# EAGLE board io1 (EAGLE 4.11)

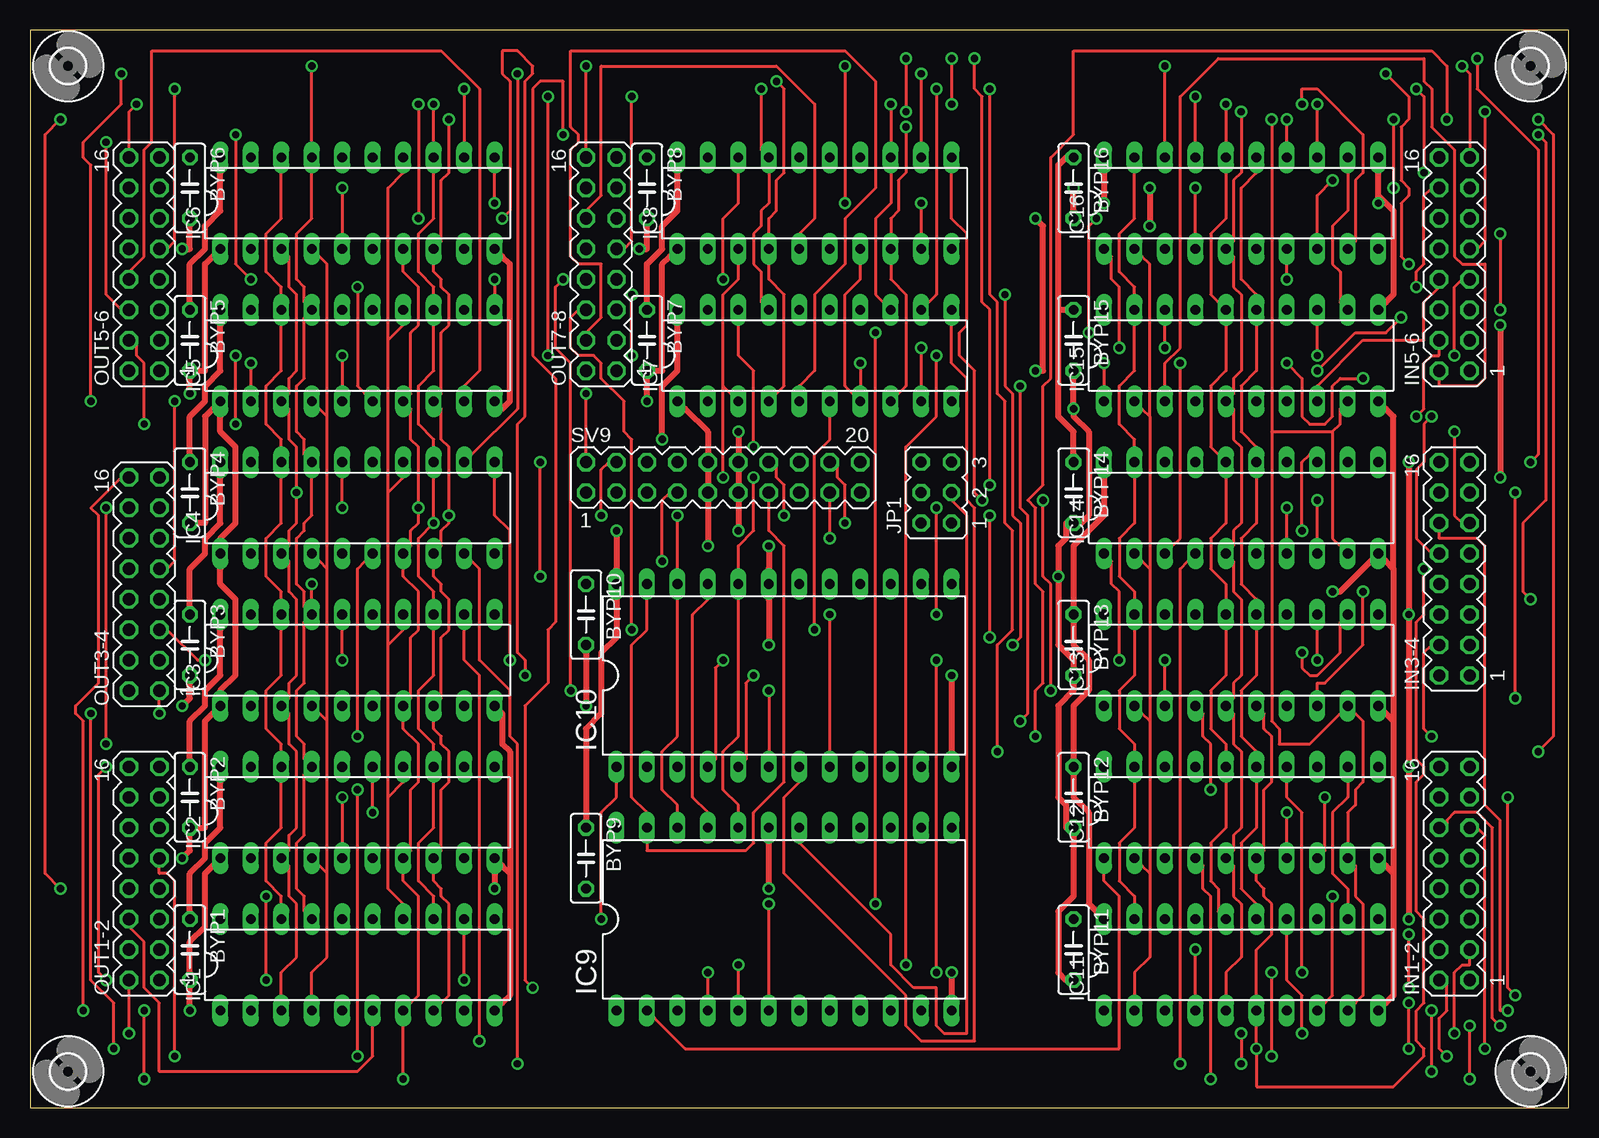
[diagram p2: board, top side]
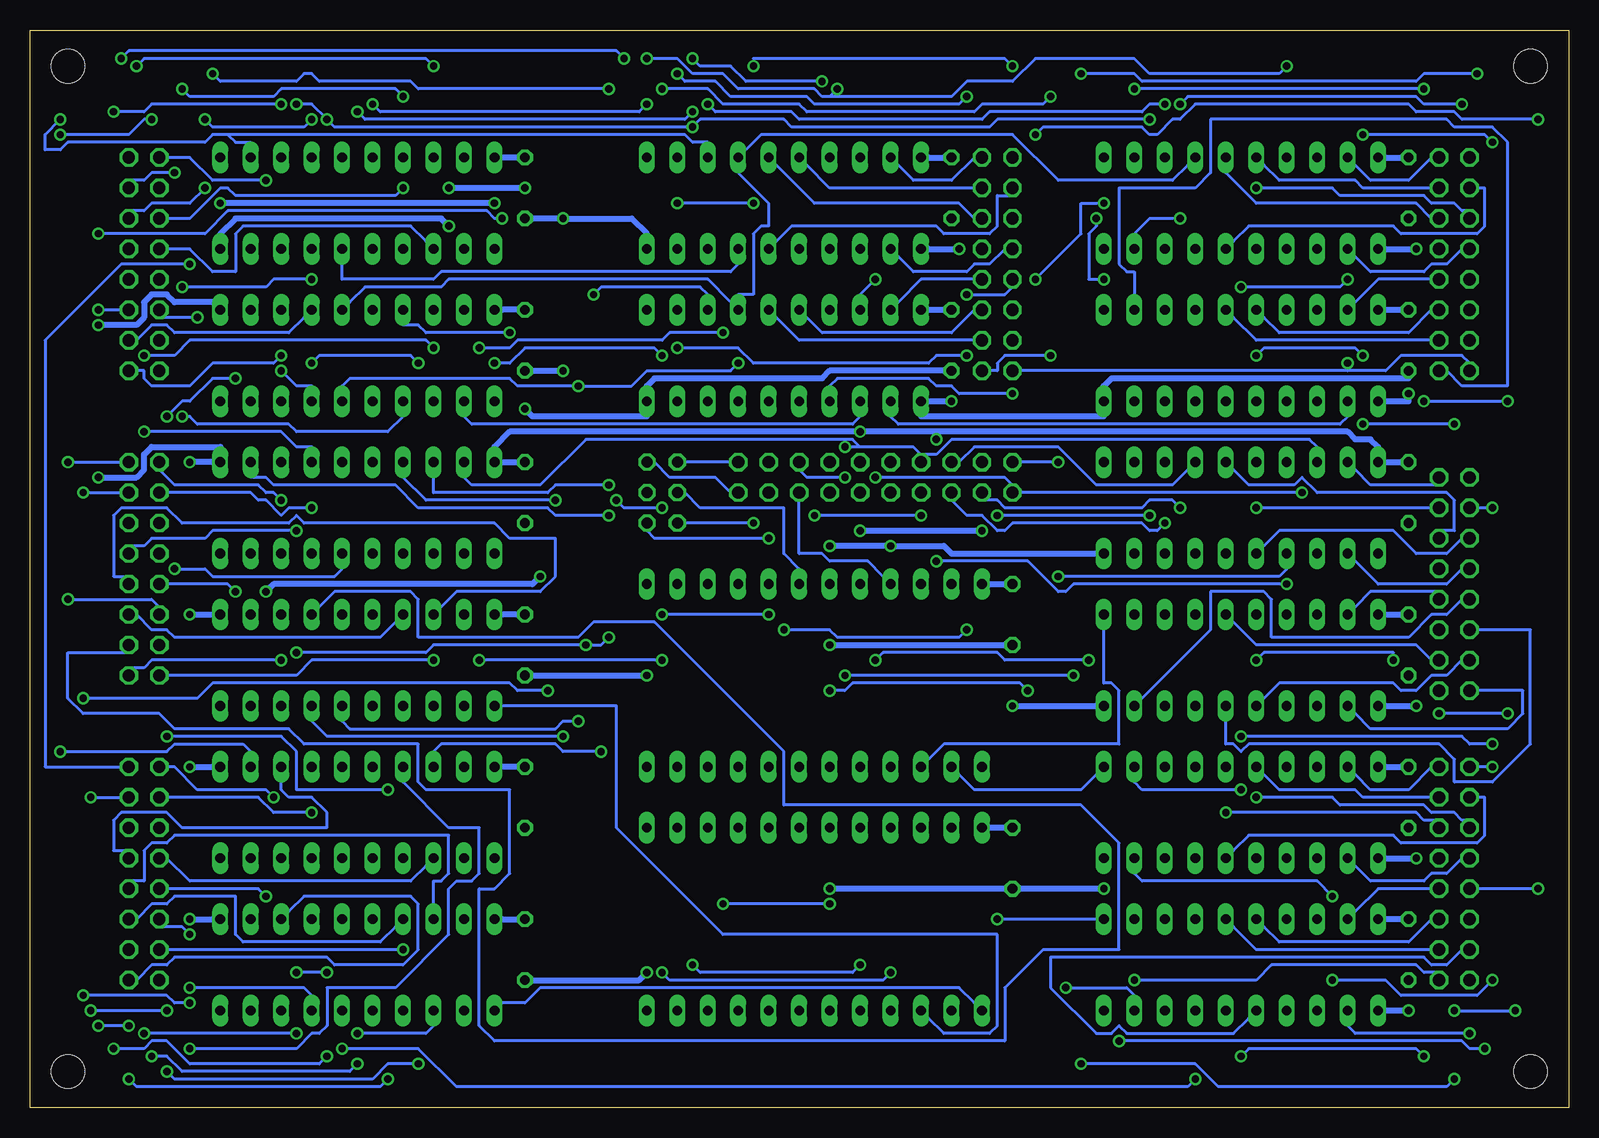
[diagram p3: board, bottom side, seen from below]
Size 128.25 x 89.84 mm. Coordinates in mm from the lower left corner, seen from the top.
Outline: 0,0 128.25,0 128.25,89.84 0,89.84 0,0
Copper layers (1*16): Top 0.035mm / dielectric 1.5mm / Bottom 0.035mm
Design rules "default": minimum track width 10mil, minimum drill 24mil, track to track 8mil, track to pad 8mil, pad to pad 8mil, via to via 8mil, smd to smd 8mil, copper to edge 40mil, drill to drill 8mil, minimum pad ring 10mil, minimum via ring 8mil, stop-mask expansion 4mil, vias tented up to drill 0mil, thermal gap 10mil
Net classes: 1 Power: width 0.508 mm, drill 0.254 mm, clearance 0.254 mm

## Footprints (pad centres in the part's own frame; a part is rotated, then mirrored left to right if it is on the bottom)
C050-025X075 = drill 0.813 octagon: 1 -2.54,0; 2 2.54,0
DIL20 = drill 0.813 long: 1 -11.43,-3.81; 2 -8.89,-3.81; 3 -6.35,-3.81; 4 -3.81,-3.81; 5 -1.27,-3.81; 6 1.27,-3.81; 7 3.81,-3.81; 8 6.35,-3.81; 9 8.89,-3.81; 10 11.43,-3.81; 11 11.43,3.81; 12 8.89,3.81; 13 6.35,3.81; 14 3.81,3.81; 15 1.27,3.81; 16 -1.27,3.81; 17 -3.81,3.81; 18 -6.35,3.81; 19 -8.89,3.81; 20 -11.43,3.81
DIL24-6 = drill 0.813 long: 1 -13.97,-7.62; 2 -11.43,-7.62; 3 -8.89,-7.62; 4 -6.35,-7.62; 5 -3.81,-7.62; 6 -1.27,-7.62; 7 1.27,-7.62; 8 3.81,-7.62; 9 6.35,-7.62; 10 8.89,-7.62; 11 11.43,-7.62; 12 13.97,-7.62; 13 13.97,7.62; 14 11.43,7.62; 15 8.89,7.62; 16 6.35,7.62; 17 3.81,7.62; 18 1.27,7.62; 19 -1.27,7.62; 20 -3.81,7.62; 21 -6.35,7.62; 22 -8.89,7.62; 23 -11.43,7.62; 24 -13.97,7.62
MA08-2 = drill 1.016 octagon: 1 -8.89,-1.27; 2 -8.89,1.27; 3 -6.35,-1.27; 4 -6.35,1.27; 5 -3.81,-1.27; 6 -3.81,1.27; 7 -1.27,-1.27; 8 -1.27,1.27; 9 1.27,-1.27; 10 1.27,1.27; 11 3.81,-1.27; 12 3.81,1.27; 13 6.35,-1.27; 14 6.35,1.27; 15 8.89,-1.27; 16 8.89,1.27
JP3Q = drill 0.914 octagon: 1 -2.54,-1.27; 2 -2.54,1.27; 3 0,-1.27; 4 0,1.27; 5 2.54,-1.27; 6 2.54,1.27
MA10-2 = drill 1.016 octagon: 1 -11.43,-1.27; 2 -11.43,1.27; 3 -8.89,-1.27; 4 -8.89,1.27; 5 -6.35,-1.27; 6 -6.35,1.27; 7 -3.81,-1.27; 8 -3.81,1.27; 9 -1.27,-1.27; 10 -1.27,1.27; 11 1.27,-1.27; 12 1.27,1.27; 13 3.81,-1.27; 14 3.81,1.27; 15 6.35,-1.27; 16 6.35,1.27; 17 8.89,-1.27; 18 8.89,1.27; 19 11.43,-1.27; 20 11.43,1.27
2,8 = hole 2.8: 0,0

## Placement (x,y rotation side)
BYP1  .01uf  [C050-025X075]  13.33,13.17 270 top
BYP2  .01uf  [C050-025X075]  13.33,25.87 270 top
BYP3  .01uf  [C050-025X075]  13.33,38.57 270 top
BYP4  .01uf  [C050-025X075]  13.33,51.27 270 top
BYP5  .01uf  [C050-025X075]  13.33,63.97 270 top
BYP6  .01uf  [C050-025X075]  13.33,76.67 270 top
BYP7  .01uf  [C050-025X075]  51.43,63.97 270 top
BYP8  .01uf  [C050-025X075]  51.43,76.67 270 top
BYP9  .01uf  [C050-025X075]  46.35,20.79 270 top
BYP10  .01uf  [C050-025X075]  46.35,41.11 270 top
BYP11  .01uf  [C050-025X075]  86.99,13.17 270 top
BYP12  .01uf  [C050-025X075]  86.99,25.87 270 top
BYP13  .01uf  [C050-025X075]  86.99,38.57 270 top
BYP14  .01uf  [C050-025X075]  86.99,51.27 270 top
BYP15  .01uf  [C050-025X075]  86.99,63.97 270 top
BYP16  .01uf  [C050-025X075]  86.99,76.67 270 top
IC1  74LS374N  [DIL20]  27.3,11.9 0 top
IC2  74LS374N  [DIL20]  27.3,24.6 0 top
IC3  74LS374N  [DIL20]  27.3,37.3 0 top
IC4  74LS374N  [DIL20]  27.3,50 0 top
IC5  74LS374N  [DIL20]  27.3,62.7 0 top
IC6  74LS374N  [DIL20]  27.3,75.4 0 top
IC7  74LS374N  [DIL20]  65.4,62.7 0 top
IC8  74LS374N  [DIL20]  65.4,75.4 0 top
IC9  74154N  [DIL24-6]  62.86,15.71 0 top
IC10  74154N  [DIL24-6]  62.86,36.03 0 top
IC11  74LS373N  [DIL20]  100.96,11.9 0 top
IC12  74LS373N  [DIL20]  100.96,24.6 0 top
IC13  74LS373N  [DIL20]  100.96,37.3 0 top
IC14  74LS373N  [DIL20]  100.96,50 0 top
IC15  74LS373N  [DIL20]  100.96,62.7 0 top
IC16  74LS373N  [DIL20]  100.96,75.4 0 top
IN1-2  [MA08-2]  118.74,19.52 90 top
IN3-4  [MA08-2]  118.74,44.92 90 top
IN5-6  [MA08-2]  118.74,70.32 90 top
JP1  [JP3Q]  75.56,51.27 90 top
OUT1-2  [MA08-2]  9.52,19.52 90 top
OUT3-4  [MA08-2]  9.52,43.65 90 top
OUT5-6  [MA08-2]  9.52,70.32 90 top
OUT7-8  [MA08-2]  47.62,70.32 90 top
SV9  [MA10-2]  57.78,52.54 0 top
U$1  [2,8]  125.09,3.01 0 top
U$2  [2,8]  125.09,86.83 0 top
U$3  [2,8]  3.17,86.83 0 top
U$4  [2,8]  3.17,3.01 0 top

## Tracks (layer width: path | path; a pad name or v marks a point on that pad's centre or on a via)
GND  (via drill 0.61)
  Top 0.508: 113.66,19.52 113.66,9.36 113.02,8.73 IC11.10 | 113.66,19.52 113.02,20.15 IC12.10 | 113.66,32.22 113.02,32.85 IC13.10 | 113.66,32.22 113.66,19.52 | 113.66,44.92 113.02,45.55 IC14.10 111.75,45.55 109.21,43.02 v108.58,43.02 | 113.66,44.92 113.66,32.22 | 113.66,44.92 113.66,57.62 113.02,58.25 IC15.10 | v76.83,11.27 76.83,9.36 IC9.12 | v76.83,36.03 76.83,29.68 IC10.12 | BYP11.2 86.35,10.63 85.72,11.27 85.72,16.34 86.99,17.61 86.99,22.7 BYP12.2 86.35,23.33 86.35,25.23 85.72,25.87 85.72,33.49 86.99,34.76 86.99,35.39 BYP13.2 86.99,36.66 86.99,37.3 85.72,38.57 v85.72,44.28 85.72,46.82 86.35,47.46 86.35,48.73 BYP14.2 87.62,48.73 88.26,49.37 88.26,56.35 86.99,57.62 v86.99,58.25 86.99,60.8 BYP15.2 | v93.34,76.67 v93.34,73.5 | v86.99,76.67 86.99,74.77 BYP16.2 | v83.81,61.43 84.45,61.43 84.45,73.5 v83.81,74.13 | v12.7,33.49 13.33,34.12 13.33,35.39 BYP3.2 | v13.33,8.09 13.33,10 BYP1.2 13.33,11.27 13.33,13.81 14.6,15.08 14.6,19.52 15.24,20.15 IC2.1 | v12.7,20.79 13.33,21.42 13.33,22.7 BYP2.2 13.97,23.33 14.6,23.33 14.6,32.22 15.24,32.85 IC3.1 15.87,34.76 17.14,36.03 17.14,42.38 15.87,43.65 15.87,44.92 IC4.1 15.87,47.46 17.14,48.73 17.14,55.08 15.87,56.35 15.87,57.62 IC5.1 15.24,58.25 14.6,57.62 14.6,48.73 13.97,48.73 BYP4.2 | v12.7,71.59 13.33,71.59 13.33,73.5 BYP6.2 | v13.33,59.52 13.33,60.8 BYP5.2 13.97,61.43 14.6,61.43 14.6,70.32 15.24,70.95 IC6.1 | 40,19.52 40,9.36 39.37,8.73 IC1.10 | 40,19.52 39.37,20.15 IC2.10 38.73,19.52 v38.73,18.25 | v61.59,18.25 61.59,22.06 IC9.19 | v50.8,71.59 51.43,71.59 51.43,73.5 BYP8.2 | IC6.10 39.37,70.95 40,70.32 40,58.89 39.37,58.25 IC5.10
  Top 0.508: v51.43,58.89 51.43,60.8 BYP7.2 52.07,61.43 52.7,61.43 52.7,70.32 53.34,70.95 IC8.1 | v46.35,33.49 46.35,37.94 BYP10.2 | v56.51,46.82 56.51,50.63 SV9.9 56.51,51.91 56.51,53.17 SV9.10 56.51,54.45 56.51,56.35 54.61,58.25 IC7.1 | v61.59,46.82 61.59,44.92 IC10.19 61.59,42.38 v61.59,38.57 | 40,19.52 40,29.68 39.37,30.31 39.37,32.85 IC3.10
  Bottom 0.508: v76.83,11.27 77.46,10.63 86.35,10.63 BYP11.2 | v76.83,36.03 86.35,36.03 BYP13.2 | v86.99,58.25 86.35,57.62 76.83,57.62 IC7.10 76.83,60.16 76.19,60.8 62.23,60.8 61.59,61.43 52.07,61.43 BYP7.2 | IC8.10 76.83,72.86 78.1,74.13 v83.81,74.13 86.35,74.13 BYP16.2 | v93.34,73.5 93.97,74.13 111.12,74.13 112.39,72.86 IC16.10 | v86.99,76.67 v93.34,76.67 | v83.81,61.43 86.35,61.43 BYP15.2 | v108.58,43.02 107.94,43.65 86.35,43.65 v85.72,44.28 | v12.7,33.49 15.24,33.49 IC3.1 | v13.33,8.09 15.24,8.09 IC1.1 | v12.7,20.79 15.24,20.79 IC2.1 | v12.7,71.59 15.24,71.59 IC6.1 | v13.33,59.52 13.33,58.89 15.24,58.89 IC5.1 | v38.73,18.25 45.72,18.25 BYP9.2 46.98,18.25 v61.59,18.25 | v50.8,71.59 53.34,71.59 IC8.1 | v51.43,58.89 53.34,58.89 IC7.1 53.97,57.62 38.73,57.62 IC5.10 38.73,60.16 38.1,60.8 13.33,60.8 BYP5.2 | v46.35,33.49 39.37,33.49 IC3.10 | IC4.10 39.37,46.19 51.43,46.19 52.07,46.82 v56.51,46.82 v61.59,46.82 | v61.59,38.57 46.98,38.57 BYP10.2
IN00
  Bottom 0.254: IC9.1 49.53,8.73 50.8,10 85.72,10 86.99,8.73 88.89,8.73 IC11.1
IN01
  Top 0.254: IC9.2 52.07,7.46 54.61,4.92 90.8,4.92 90.8,17.61 89.53,18.88 89.53,19.52 IC12.1
IN02
  Bottom 0.254: IC9.3 53.34,7.46 52.07,6.18 48.26,6.18 47.62,6.82 47.62,14.44 70.48,14.44 79.37,23.33 79.37,33.49 88.89,33.49 IC13.1
IN03  (via drill 0.61)
  Top 0.254: v56.51,11.27 56.51,9.36 IC9.4 | v75.56,11.27 v75.56,37.3 | v90.8,37.3 90.8,43.02 90.16,43.65 90.16,45.55 IC14.1
  Bottom 0.254: v56.51,11.27 57.15,10.63 74.92,10.63 v75.56,11.27 | v75.56,37.3 v90.8,37.3
IN04  (via drill 0.61)
  Top 0.254: v59.05,11.9 59.05,9.36 IC9.5 | v73.02,11.9 73.02,55.08 75.56,57.62 v75.56,62.7 | v89.53,62.06 89.53,60.16 IC15.1
  Bottom 0.254: v59.05,11.9 59.69,11.27 72.38,11.27 v73.02,11.9 | v75.56,62.7 76.19,63.34 86.99,63.34 88.26,62.06 v89.53,62.06
IN05  (via drill 0.61)
  Top 0.254: v61.59,16.98 61.59,9.36 IC9.6 | v70.48,16.98 v70.48,64.61 | v90.8,63.34 90.8,68.41 90.16,69.05 90.16,70.95 IC16.1
  Bottom 0.254: v61.59,16.98 v70.48,16.98 | v70.48,64.61 74.92,64.61 75.56,63.97 87.62,63.97 88.26,63.34 v90.8,63.34
ISEL
  Top 0.254: IC9.18 64.13,22.06 71.75,14.44 71.75,11.9 73.66,10 75.56,10 75.56,6.82 76.19,6.18 78.1,6.18 78.1,49.37 76.83,50.63 JP1.3
N$1
  Bottom 0.254: IC12.3 95.24,20.15 96.52,18.88 114.93,18.88 116.83,20.79 IN1-2.10
N$2  (via drill 0.61)
  Top 0.254: v98.42,2.38 98.42,17.61 97.78,18.25 97.78,20.15 IC12.4 | v120.01,2.38 v120.01,6.82 | v122.55,6.82 121.91,7.46 121.91,23.33 120.64,24.6 118.74,24.6 118.1,23.96 118.1,23.33 IN1-2.12
  Bottom 0.254: v98.42,2.38 99.05,1.74 119.38,1.74 v120.01,2.38 | v120.01,6.82 v122.55,6.82
N$7  (via drill 0.61)
  Top 0.254: v104.77,24.6 104.77,22.06 IC12.7
  Bottom 0.254: v104.77,24.6 107.94,24.6 109.21,25.87 116.83,25.87 IN1-2.14
N$8  (via drill 0.61)
  Top 0.254: v107.94,25.87 107.94,21.42 IC12.8
  Bottom 0.254: v107.94,25.87 108.58,26.5 114.3,26.5 116.2,28.41 116.83,28.41 IN1-2.16
N$9  (via drill 0.61)
  Top 0.254: v108.58,17.61 108.58,9.36 107.94,8.73 IC11.8
  Bottom 0.254: v108.58,17.61 109.21,18.25 116.83,18.25 IN1-2.8
N$10  (via drill 0.61)
  Top 0.254: v114.93,10 v114.93,14.44
  Bottom 0.254: v114.93,14.44 115.56,15.08 117.47,15.08 IN1-2.6 | v114.93,10 105.41,10 104.77,9.36 IC11.7
N$11  (via drill 0.61)
  Top 0.254: v97.15,13.17 97.15,9.36 IC11.4
  Bottom 0.254: v97.15,13.17 116.83,13.17 IN1-2.4
N$12  (via drill 0.61)
  Top 0.254: v100.96,6.18 v100.96,3.64 | v118.1,4.28 117.47,4.92 117.47,7.46 118.1,8.09 118.1,10.63 IN1-2.2
  Bottom 0.254: v100.96,6.18 95.24,6.18 94.61,6.82 IC11.3 | v100.96,3.64 101.59,3.01 115.56,3.01 116.83,4.28 v118.1,4.28
N$13
  Bottom 0.254: IC11.13 106.67,16.34 105.41,17.61 96.52,17.61 95.88,16.98 95.88,13.17 97.15,11.9 102.86,11.9 103.5,12.54 116.2,12.54 116.83,11.9 118.1,11.9 119.38,10.63 IN1-2.1
N$14  (via drill 0.61)
  Top 0.254: v106.04,6.18 106.04,9.36 104.77,10.63 104.77,14.44 IC11.14 | v118.74,6.18 118.74,11.27 119.38,11.9 120.01,11.9 120.01,12.54 IN1-2.3
  Bottom 0.254: v106.04,6.18 v118.74,6.18
N$15
  Bottom 0.254: IC11.17 97.78,15.08 99.05,13.81 110.48,13.81 111.12,14.44 111.12,17.61 116.2,17.61 116.83,16.98 118.1,16.98 119.38,15.71 IN1-2.5
N$16
  Bottom 0.254: IC11.18 94.61,16.98 94.61,18.88 93.97,18.88 93.34,19.52 93.34,22.7 116.2,22.7 116.83,22.06 118.1,22.06 118.74,21.42 118.74,18.88 120.01,18.88 IN1-2.7
N$17
  Bottom 0.254: IC12.13 107.31,27.14 107.31,26.5 106.67,25.87 104.77,25.87 103.5,24.6 103.5,23.33 115.56,23.33 116.83,24.6 120.64,24.6 121.28,23.96 121.28,21.42 120.01,21.42 IN1-2.9
N$18  (via drill 0.61)
  Top 0.254: v121.28,4.92 121.28,22.7 120.64,23.33 IN1-2.11 | v103.5,4.28 v103.5,11.27 | v106.04,11.27 106.04,24.6 104.77,25.87 104.77,27.14 IC12.14
  Bottom 0.254: v121.28,4.92 118.74,4.92 118.1,5.55 116.83,5.55 114.93,3.64 104.13,3.64 v103.5,4.28 | v103.5,11.27 v106.04,11.27
N$19  (via drill 0.61)
  Top 0.254: v123.19,25.87 123.19,10 v123.82,9.36 | v114.93,4.92 v114.93,8.73
  Bottom 0.254: v123.19,25.87 120.64,25.87 IN1-2.13 | v123.82,9.36 116.83,9.36 116.2,8.73 v114.93,8.73 | v114.93,4.92 106.04,4.92 104.77,6.18 104.13,6.18 103.5,6.82 103.5,10 97.78,10 93.34,14.44 93.34,18.25 92.7,18.88 91.44,18.88 90.8,19.52 90.8,23.33 93.34,23.33 97.15,27.14 IC12.17
N$20  (via drill 0.61)
  Top 0.254: v80.64,29.68 80.64,38.57 81.91,39.84 81.91,48.09 81.27,48.73 81.27,58.89 80.64,59.52 80.64,67.14 80,67.78 v80,84.92 | v113.02,86.19 114.93,84.29 114.93,82.39 114.3,81.75 114.3,77.3 114.93,76.67 114.93,76.03 114.3,75.4 114.3,70.95 v114.93,70.32
  Bottom 0.254: v80.64,29.68 83.81,29.68 84.45,30.31 93.97,30.31 94.61,29.68 IC12.18 | v80,84.92 95.88,84.92 96.52,85.56 104.13,85.56 104.77,86.19 105.41,86.19 106.04,85.56 112.39,85.56 v113.02,86.19 | v114.93,70.32 120.64,70.32 126.99,63.97 126.99,28.41 120.64,28.41 IN1-2.15
N$26  (via drill 0.61)
  Top 0.254: v18.41,62.06 18.41,60.16 IC5.2
  Bottom 0.254: IC7.2 56.51,57.62 55.88,56.98 19.04,56.98 18.41,57.62 IC5.2 | 18.41,61.43 15.24,61.43 13.97,62.7 8.89,62.7 8.25,62.06 OUT5-6.2 | 18.41,61.43 45.72,61.43 OUT7-8.2 | 18.41,61.43 v18.41,62.06
N$29  (via drill 0.61)
  Top 0.254: v95.88,62.06 95.88,47.46 95.24,46.82 IC14.3 | v104.77,62.06 106.04,60.8 106.04,57.62 106.67,56.98 107.94,56.98 108.58,57.62 108.58,60.16 109.21,60.8 v111.12,60.8 | v116.83,57.62 116.2,56.98 116.2,53.81 115.56,53.17 115.56,47.46 116.83,46.19 IN3-4.10
  Bottom 0.254: v95.88,62.06 96.52,62.7 104.13,62.7 v104.77,62.06 | v111.12,60.8 113.02,60.8 114.93,58.89 115.56,58.89 v116.83,57.62
N$30  (via drill 0.61)
  Top 0.254: v95.88,3.64 95.88,44.92 96.52,45.55 IC14.4 | v116.83,3.01 v116.83,8.09 | v123.19,8.09 122.55,8.09 122.55,23.96 121.28,25.23 121.28,46.82 120.64,47.46 117.47,47.46 117.47,48.09 IN3-4.12
  Bottom 0.254: v95.88,3.64 98.42,3.64 99.69,2.38 116.2,2.38 v116.83,3.01 | v116.83,8.09 v123.19,8.09
N$31  (via drill 0.61)
  Top 0.254: v104.77,50 104.77,47.46 IC14.7
  Bottom 0.254: v104.77,50 106.67,50 107.31,49.37 108.58,50.63 109.21,50.63 109.85,51.27 116.83,51.27 IN3-4.14
N$32  (via drill 0.61)
  Top 0.254: v107.31,50.63 107.31,47.46 IC14.8
  Bottom 0.254: v107.31,50.63 107.94,51.27 108.58,51.27 109.21,51.91 116.2,51.91 117.47,53.17 IN3-4.16
N$33  (via drill 0.61)
  Top 0.254: v37.46,5.55 37.46,36.03 36.19,37.3 36.19,39.84 IC3.12 | v6.98,4.92 6.98,8.73 5.08,10.63 v5.08,32.85 | v10.79,32.85 10.79,34.12 OUT3-4.1
  Bottom 0.254: v37.46,5.55 8.89,5.55 8.25,4.92 v6.98,4.92 | v5.08,32.85 v10.79,32.85
N$34
  Bottom 0.254: IC3.15 27.93,40.48 26.03,38.57 12.7,38.57 11.43,37.3 OUT3-4.3
N$35  (via drill 0.61)
  Top 0.254: v14.6,37.3 13.97,37.3 11.43,39.84 OUT3-4.5 | v26.03,37.3 26.03,39.84 IC3.16
  Bottom 0.254: v14.6,37.3 14.6,37.94 25.39,37.94 v26.03,37.3
N$36
  Bottom 0.254: IC3.19 17.77,41.74 16.5,43.02 10.79,43.02 OUT3-4.7
N$37  (via drill 0.61)
  Top 0.254: v94.61,37.3 94.61,34.76 IC13.3
  Bottom 0.254: v94.61,37.3 104.77,37.3 106.04,36.03 116.83,36.03 IN3-4.2
N$38  (via drill 0.61)
  Top 0.254: v116.83,30.95 116.2,31.58 116.2,37.94 116.83,38.57 IN3-4.4 | v98.42,26.5 98.42,30.31 97.78,30.95 97.78,32.85 IC13.4
  Bottom 0.254: v116.83,30.95 107.31,30.95 106.04,29.68 106.04,26.5 v98.42,26.5
N$39  (via drill 0.61)
  Top 0.254: v125.09,42.38 124.45,43.02 124.45,48.73 126.36,50.63 126.36,80.48 v125.72,81.11 | v118.1,82.39 118.1,86.83 116.83,88.1 86.99,88.1 86.99,81.11 85.08,79.21 85.08,60.8 84.45,60.16 84.45,51.91 83.18,50.63 83.81,50 83.81,43.65 84.45,43.02 84.45,35.39 83.81,34.76 v83.81,30.95
  Bottom 0.254: v125.09,42.38 118.1,42.38 117.47,41.74 IN3-4.6 | v125.72,81.11 120.01,81.11 118.74,82.39 v118.1,82.39 | v83.81,30.95 103.5,30.95 104.77,32.22 IC13.7
N$40  (via drill 0.61)
  Top 0.254: v111.12,43.02 111.12,38.57 107.94,35.39 107.31,35.39 107.31,34.76 IC13.8
  Bottom 0.254: v111.12,43.02 111.75,43.65 116.83,43.65 IN3-4.8
N$41  (via drill 0.61)
  Top 0.254: v106.04,48.09 106.04,53.81 106.67,54.45 IC14.13
  Bottom 0.254: v106.04,48.09 113.02,48.09 113.66,47.46 118.1,47.46 118.74,46.82 120.01,46.82 IN3-4.9
N$42  (via drill 0.61)
  Top 0.254: v118.74,56.35 118.74,49.37 119.38,48.73 IN3-4.11
  Bottom 0.254: v118.74,56.35 107.31,56.35 106.04,55.08 104.77,55.08 IC14.14
N$43  (via drill 0.61)
  Top 0.254: v123.82,34.12 v123.82,51.27 | v85.08,34.76 85.08,43.65 84.45,44.28 v84.45,50.63
  Bottom 0.254: v123.82,51.27 120.64,51.27 IN3-4.13 | v123.82,34.12 114.3,34.12 113.02,35.39 88.26,35.39 87.62,34.76 v85.08,34.76 | v84.45,50.63 95.24,50.63 97.15,52.54 IC14.17
N$44  (via drill 0.61)
  Top 0.254: v80,51.91 80,66.51 79.37,67.14 79.37,84.29 78.73,84.92 v78.73,87.47 | v120.64,87.47 120.64,84.92 125.72,79.84 125.72,54.45 v125.09,53.81
  Bottom 0.254: v80,51.91 84.45,51.91 85.08,51.27 94.61,51.27 94.61,52.54 IC14.18 | v78.73,87.47 79.37,88.1 120.01,88.1 v120.64,87.47 | v125.09,53.81 120.64,53.81 IN3-4.15
N$45  (via drill 0.61)
  Top 0.254: v107.31,37.3 107.31,39.84 IC13.13
  Bottom 0.254: v107.31,37.3 118.1,37.3 118.74,36.66 120.01,36.66 IN3-4.1
N$46
  Bottom 0.254: IC13.14 104.13,41.74 102.86,43.02 96.52,43.02 95.88,42.38 95.88,39.2 82.55,39.2 81.27,40.48 76.19,40.48 65.4,29.68 65.4,25.23 40.64,25.23 37.46,22.06 37.46,13.17 43.81,13.17 46.98,10 46.98,5.55 89.53,5.55 90.8,6.82 90.8,18.25 89.53,18.25 88.26,19.52 88.26,26.5 95.24,26.5 95.88,27.14 95.88,30.31 105.41,30.31 106.67,31.58 116.2,31.58 117.47,32.85 123.82,32.85 125.09,34.12 125.09,37.94 120.01,37.94 IN3-4.3
N$47
  Bottom 0.254: IC13.17 97.78,40.48 99.05,39.2 116.2,39.2 116.83,39.84 118.1,39.84 119.38,41.11 IN3-4.5
N$48
  Bottom 0.254: IC13.18 93.97,41.74 92.7,43.02 85.72,43.02 84.45,44.28 84.45,47.46 88.26,47.46 89.53,48.73 105.41,48.73 106.04,49.37 106.67,48.73 115.56,48.73 116.83,50 120.64,50 121.28,49.37 121.28,44.28 120.01,44.28 IN3-4.7
N$49
  Bottom 0.254: IC3.5 25.39,34.12 24.12,35.39 14.6,35.39 13.97,34.76 12.7,34.76 11.43,36.03 10.16,36.03 8.89,37.3 OUT3-4.4
N$50
  Bottom 0.254: IC3.6 28.57,32.22 28.57,30.31 27.93,30.31 27.3,29.68 26.66,30.31 10.79,30.31 9.52,29.04 9.52,27.14 6.34,27.14 3.17,30.31 3.17,39.84 7.62,39.84 OUT3-4.6
N$51
  Bottom 0.254: IC3.2 17.77,32.85 16.5,31.58 5.08,31.58 3.8,32.85 3.8,34.76 7.62,34.76 OUT3-4.2
N$52
  Bottom 0.254: IC3.9 35.55,34.12 29.84,39.84 29.84,43.02 25.39,43.02 24.76,42.38 24.76,39.2 13.33,39.2 11.43,41.11 10.16,41.11 8.89,42.38 OUT3-4.8
N$53  (via drill 0.61)
  Top 0.254: v36.19,10.63 36.19,14.44 IC1.12
  Bottom 0.254: v36.19,10.63 26.03,10.63 24.76,11.9 12.7,11.9 12.06,11.27 10.79,11.27 OUT1-2.1
N$54
  Bottom 0.254: IC1.15 27.93,15.08 26.03,13.17 11.43,13.17 OUT1-2.3
N$55
  Bottom 0.254: IC1.16 25.39,15.08 24.12,13.81 13.33,13.81 11.43,15.71 OUT1-2.5
N$56
  Bottom 0.254: IC1.19 17.77,16.34 15.87,18.25 11.43,18.25 OUT1-2.7
N$57  (via drill 0.61)
  Top 0.254: v8.25,6.18 8.25,10 OUT1-2.2
  Bottom 0.254: v8.25,6.18 17.77,6.18 18.41,6.82 IC1.2
N$58
  Bottom 0.254: IC1.5 26.66,7.46 27.93,6.18 36.83,6.18 37.46,6.82 38.1,6.18 39.37,6.18 43.18,10 43.18,12.54 12.06,12.54 11.43,11.9 10.16,11.9 8.89,13.17 OUT1-2.4
N$59
  Top 0.254: IC1.6 28.57,6.82 28.57,4.28 27.3,3.01 10.79,3.01 10.79,8.73 9.52,10 9.52,13.81 8.25,15.08 OUT1-2.6
N$60  (via drill 0.61)
  Top 0.254: v41.91,10 41.27,10.63 41.27,33.49 43.18,35.39 43.18,39.84 43.81,40.48 43.81,60.8 41.91,62.7 41.91,84.92 42.54,85.56 44.45,85.56 v44.45,81.11 | v2.54,82.39 1.27,81.11 1.27,19.52 v2.54,18.25
  Bottom 0.254: v41.91,10 36.83,10 36.19,9.36 IC1.9 | v44.45,81.11 43.81,81.75 35.55,81.75 34.92,81.11 34.29,81.11 33.02,82.39 32.38,82.39 31.11,83.66 13.33,83.66 12.7,83.02 9.52,83.02 8.89,82.39 v2.54,82.39 | v2.54,18.25 7.62,18.25 OUT1-2.8
N$61
  Bottom 0.254: IC2.19 17.77,27.77 16.5,26.5 13.33,26.5 11.43,28.41 OUT1-2.15
N$62
  Bottom 0.254: IC2.16 25.39,27.77 24.12,26.5 17.77,26.5 17.14,25.87 11.43,25.87 OUT1-2.13
N$63  (via drill 0.61)
  Top 0.254: v28.57,24.6 28.57,27.14 IC2.15
  Bottom 0.254: v28.57,24.6 12.7,24.6 12.06,23.96 10.79,23.96 OUT1-2.11
N$64  (via drill 0.61)
  Top 0.254: v27.3,4.28 v27.3,26.5 | v12.06,4.28 12.06,18.88 11.43,19.52 10.79,19.52 10.79,20.15 OUT1-2.9
  Bottom 0.254: v27.3,26.5 35.55,26.5 36.19,27.14 IC2.12 | v27.3,4.28 26.66,4.92 12.7,4.92 v12.06,4.28
N$65
  Bottom 0.254: IC2.2 17.77,20.15 16.5,18.88 12.06,18.88 11.43,19.52 10.16,19.52 8.89,20.79 OUT1-2.10
N$66  (via drill 0.61)
  Top 0.254: v26.03,25.87 26.03,22.06 IC2.5
  Bottom 0.254: v26.03,25.87 19.68,25.87 19.04,25.23 12.06,25.23 11.43,24.6 9.52,24.6 8.89,23.96 8.25,23.96 OUT1-2.12
N$67
  Bottom 0.254: IC2.6 27.93,21.42 26.66,22.7 14.6,22.7 13.97,22.06 7.62,22.06 6.98,22.7 6.98,25.87 7.62,25.87 OUT1-2.14
N$68  (via drill 0.61)
  Top 0.254: v6.34,28.41 5.71,27.77 5.71,11.27 v6.34,10.63 | v19.68,10.63 v19.68,17.61
  Bottom 0.254: v6.34,28.41 7.62,28.41 OUT1-2.16 | v6.34,10.63 7.62,9.36 13.97,9.36 15.24,10.63 v19.68,10.63 | v19.68,17.61 20.95,18.88 35.55,18.88 36.19,19.52 IC2.9
N$69
  Bottom 0.254: IC4.2 17.77,45.55 15.87,43.65 10.16,43.65 8.89,44.92 OUT3-4.10
N$70
  Bottom 0.254: IC4.5 25.39,46.82 24.12,48.09 14.6,48.09 12.7,46.19 10.16,46.19 8.89,47.46 OUT3-4.12
N$71  (via drill 0.61)
  Top 0.254: v27.3,30.95 27.3,44.92 27.93,45.55 IC4.6 | v6.34,30.31 v6.34,50
  Bottom 0.254: v27.3,30.95 8.89,30.95 8.25,30.31 v6.34,30.31 | v6.34,50 7.62,50 OUT3-4.14
N$72  (via drill 0.61)
  Top 0.254: v40.64,3.64 40.64,30.31 40,30.95 40,34.76 37.46,37.3 37.46,44.92 36.83,45.55 IC4.9 | v9.52,2.38 v9.52,8.09 | v4.44,8.09 4.44,32.22 3.8,32.85 3.8,33.49 5.71,35.39 5.71,49.37 5.08,50 7.62,52.54 OUT3-4.16
  Bottom 0.254: v40.64,3.64 31.11,3.64 29.2,1.74 10.16,1.74 v9.52,2.38 | v9.52,8.09 v4.44,8.09
N$73
  Bottom 0.254: IC4.19 17.77,53.17 16.5,51.91 10.79,51.91 OUT3-4.15
N$74  (via drill 0.61)
  Top 0.254: v26.03,50 26.03,52.54 IC4.16
  Bottom 0.254: v26.03,50 11.43,50 OUT3-4.13
N$75
  Bottom 0.254: IC4.15 27.93,53.17 26.66,51.91 22.86,51.91 22.22,52.54 20.95,51.27 10.16,51.27 9.52,50.63 9.52,48.09 10.79,48.09 OUT3-4.11
N$76  (via drill 0.61)
  Top 0.254: v12.06,58.89 12.06,45.55 11.43,44.92 OUT3-4.9 | v5.08,58.89 5.08,78.58 4.44,79.21 4.44,80.48 7.62,83.66 v7.62,86.19 | v40.64,86.19 40.64,58.25 36.83,54.45 IC4.12
  Bottom 0.254: v12.06,58.89 v5.08,58.89 | v7.62,86.19 12.06,86.19 12.7,85.56 35.55,85.56 36.19,86.19 v40.64,86.19
N$77
  Bottom 0.254: IC16.3 95.24,72.22 96.52,73.5 110.48,73.5 111.12,72.86 111.12,69.69 113.02,69.69 114.93,71.59 116.83,71.59 IN5-6.10
N$78  (via drill 0.61)
  Top 0.254: v97.15,76.67 97.15,72.86 IC16.4
  Bottom 0.254: v97.15,76.67 97.78,76.03 111.12,76.03 111.75,76.67 112.39,76.67 114.93,74.13 116.83,74.13 IN5-6.12
N$79  (via drill 0.61)
  Top 0.254: v115.56,68.41 115.56,69.69 116.2,70.32 116.2,76.03 116.83,76.67 IN5-6.14 | v104.77,69.05 104.77,70.32 IC16.7
  Bottom 0.254: v115.56,68.41 108.58,68.41 107.94,69.05 v104.77,69.05
N$80  (via drill 0.61)
  Top 0.254: v108.58,77.3 107.31,76.03 107.31,72.86 IC16.8
  Bottom 0.254: v108.58,77.3 113.02,77.3 114.93,79.21 116.83,79.21 IN5-6.16
N$81
  Bottom 0.254: IC5.12 36.19,67.78 36.19,69.69 36.83,69.69 37.46,70.32 37.46,76.67 31.11,76.67 29.84,77.94 29.84,82.39 10.16,82.39 9.52,81.75 6.34,81.75 5.08,80.48 5.08,60.16 8.89,60.16 10.16,61.43 OUT5-6.1
N$82
  Bottom 0.254: IC5.15 27.93,65.88 26.03,63.97 11.43,63.97 OUT5-6.3
N$83
  Bottom 0.254: IC5.16 25.39,65.88 24.12,64.61 13.33,64.61 11.43,66.51 OUT5-6.5
N$84
  Bottom 0.254: IC5.19 17.77,67.14 15.87,69.05 11.43,69.05 OUT5-6.7
N$85  (via drill 0.61)
  Top 0.254: v75.56,84.92 75.56,67.78 74.92,67.14 IC7.12 | v43.18,62.7 v43.18,84.29
  Bottom 0.254: v75.56,84.92 71.75,84.92 70.48,83.66 64.13,83.66 63.5,83.02 49.53,83.02 48.89,83.66 43.81,83.66 v43.18,84.29 | v43.18,62.7 46.98,62.7 47.62,62.06 47.62,61.43 48.26,61.43 OUT7-8.1
N$86
  Bottom 0.254: IC7.15 66.03,65.88 64.13,63.97 49.53,63.97 OUT7-8.3
N$87
  Bottom 0.254: IC7.16 63.5,65.88 62.23,64.61 51.43,64.61 49.53,66.51 OUT7-8.5
N$88
  Bottom 0.254: IC7.19 55.88,67.14 53.97,69.05 49.53,69.05 OUT7-8.7
N$89  (via drill 0.61)
  Top 0.254: v26.03,62.7 26.03,60.16 IC5.5 | v17.14,56.98 v17.14,62.7 | v9.52,56.98 9.52,62.06 8.89,62.7 8.89,63.97 OUT5-6.4
  Bottom 0.254: v26.03,62.7 25.39,63.34 17.77,63.34 v17.14,62.7 | v9.52,56.98 v17.14,56.98
N$90  (via drill 0.61)
  Top 0.254: v27.3,68.41 27.3,60.16 27.93,59.52 IC5.6 | v18.41,69.05 17.14,70.32 v17.14,81.11 | v6.34,80.48 6.34,67.78 7.62,66.51 OUT5-6.6
  Bottom 0.254: v27.3,68.41 19.04,68.41 v18.41,69.05 | v17.14,81.11 6.98,81.11 v6.34,80.48
N$91
  Top 0.254: IC5.9 36.19,60.16 37.46,61.43 37.46,84.92 34.29,88.1 10.16,88.1 10.16,80.48 9.52,79.84 9.52,70.95 8.25,69.69 OUT5-6.8
N$92  (via drill 0.61)
  Top 0.254: v36.19,84.92 36.19,80.48 IC6.12 | v12.06,84.92 12.06,72.22 11.43,71.59 OUT5-6.9
  Bottom 0.254: v12.06,84.92 v36.19,84.92
N$93
  Bottom 0.254: IC6.15 28.57,77.94 26.03,75.4 12.7,75.4 11.43,74.13 OUT5-6.11
N$95
  Bottom 0.254: IC6.16 25.39,78.58 24.12,77.3 17.77,77.3 17.14,76.67 11.43,76.67 OUT5-6.13
N$96
  Bottom 0.254: IC6.19 17.77,78.58 16.5,77.3 13.33,77.3 11.43,79.21 OUT5-6.15
N$97
  Bottom 0.254: IC6.2 17.77,70.95 16.5,69.69 12.06,69.69 11.43,70.32 10.16,70.32 8.89,71.59 OUT5-6.10
N$98  (via drill 0.61)
  Top 0.254: v26.03,76.67 26.03,72.86 IC6.5
  Bottom 0.254: v26.03,76.67 19.68,76.67 19.04,76.03 12.06,76.03 11.43,75.4 9.52,75.4 8.89,74.77 8.25,74.77 OUT5-6.12
N$99
  Bottom 0.254: IC6.6 27.93,72.22 26.66,73.5 14.6,73.5 13.97,72.86 7.62,72.86 6.98,73.5 6.98,76.67 7.62,76.67 OUT5-6.14
N$100  (via drill 0.61)
  Top 0.254: v32.38,83.66 v32.38,74.13 | v8.89,83.66 8.25,83.02 8.25,79.84 OUT5-6.16
  Bottom 0.254: v32.38,74.13 34.92,74.13 36.19,72.86 IC6.9 | v32.38,83.66 31.74,84.29 12.7,84.29 12.06,83.66 v8.89,83.66
N$101
  Top 0.254: IC15.3 94.61,60.16 94.61,62.06 95.88,63.34 95.88,84.29 99.05,87.47 116.2,87.47 116.2,85.56 116.83,84.92 116.83,81.75 118.74,79.84 118.74,70.95 119.38,70.32 121.28,70.32 121.28,60.8 120.64,60.16 117.47,60.16 117.47,60.8 IN5-6.2
N$102  (via drill 0.61)
  Top 0.254: v115.56,57.62 116.2,58.25 116.2,62.06 116.83,62.7 117.47,62.7 117.47,63.34 IN5-6.4
  Bottom 0.254: v115.56,57.62 114.93,57.62 114.3,56.98 106.67,56.98 106.04,56.35 98.42,56.35 97.15,57.62 IC15.4
N$103  (via drill 0.61)
  Top 0.254: v114.3,65.88 113.02,64.61 110.48,64.61 v107.31,61.43
  Bottom 0.254: v114.3,65.88 117.47,65.88 IN5-6.6 | v107.31,61.43 106.04,60.16 104.77,60.16 IC15.7
N$104
  Top 0.254: IC15.8 107.31,60.16 111.12,63.97 116.2,63.97 116.2,67.14 117.47,68.41 IN5-6.8
N$105  (via drill 0.61)
  Top 0.254: v121.28,83.02 121.28,72.22 120.64,71.59 IN5-6.9 | v107.31,83.66 107.31,80.48 IC16.13
  Bottom 0.254: v121.28,83.02 118.74,83.02 118.1,83.66 v107.31,83.66
N$106  (via drill 0.61)
  Top 0.254: v113.66,82.39 v113.66,76.67 | v104.77,82.39 104.77,80.48 IC16.14
  Bottom 0.254: v113.66,76.67 114.93,75.4 118.1,75.4 118.74,74.77 120.01,74.77 IN5-6.11 | v113.66,82.39 113.02,81.75 105.41,81.75 v104.77,82.39
N$107  (via drill 0.61)
  Top 0.254: v116.2,77.94 116.2,84.29 v115.56,84.92 | v97.15,84.29 97.15,80.48 IC16.17
  Bottom 0.254: v116.2,77.94 118.1,77.94 118.74,77.3 120.01,77.3 IN5-6.13 | v115.56,84.92 114.93,84.29 107.94,84.29 107.31,84.92 97.78,84.92 v97.15,84.29
N$108  (via drill 0.61)
  Top 0.254: v94.61,86.83 94.61,80.48 IC16.18 | v119.38,86.83 120.01,86.19 120.01,79.84 IN5-6.15
  Bottom 0.254: v94.61,86.83 95.24,87.47 118.74,87.47 v119.38,86.83
N$109  (via drill 0.61)
  Top 0.254: v107.31,62.7 107.31,65.24 IC15.13
  Bottom 0.254: v107.31,62.7 107.94,62.06 113.02,62.06 114.93,60.16 118.1,60.16 118.74,60.8 118.74,61.43 119.38,61.43 IN5-6.1
N$110
  Bottom 0.254: IC15.14 105.41,65.88 106.67,64.61 116.2,64.61 116.83,65.24 118.1,65.24 119.38,63.97 IN5-6.3
N$111  (via drill 0.61)
  Top 0.254: v88.26,64.61 88.26,73.5 v88.89,74.13 | v122.55,72.86 v122.55,66.51
  Bottom 0.254: v88.26,64.61 95.24,64.61 95.88,65.24 97.15,65.24 IC15.17 | v88.89,74.13 89.53,74.13 90.16,74.77 111.75,74.77 113.66,72.86 v122.55,72.86 | v122.55,66.51 120.64,66.51 IN5-6.5
N$112  (via drill 0.61)
  Top 0.254: v118.74,62.7 118.74,68.41 119.38,69.05 IN5-6.7 | v94.61,63.34 94.61,65.24 IC15.18
  Bottom 0.254: v118.74,62.7 116.2,62.7 114.93,63.97 95.24,63.97 v94.61,63.34
N$113
  Bottom 0.254: IC8.19 55.88,78.58 54.61,77.3 51.43,77.3 49.53,79.21 OUT7-8.15
N$114
  Bottom 0.254: IC8.16 63.5,78.58 61.59,76.67 49.53,76.67 OUT7-8.13
N$115
  Bottom 0.254: IC8.15 66.03,78.58 62.86,75.4 50.8,75.4 49.53,74.13 OUT7-8.11
N$116  (via drill 0.61)
  Top 0.254: v74.29,86.19 74.29,80.48 IC8.12 | v50.16,84.29 50.16,72.22 49.53,71.59 OUT7-8.9
  Bottom 0.254: v74.29,86.19 73.66,85.56 71.11,85.56 69.84,84.29 63.5,84.29 62.86,83.66 50.8,83.66 v50.16,84.29
N$117
  Bottom 0.254: IC8.2 55.88,70.95 54.61,69.69 50.16,69.69 49.53,70.32 48.26,70.32 46.98,71.59 OUT7-8.10
N$118
  Top 0.254: IC8.5 64.13,72.86 65.4,74.13 65.4,83.66 62.23,86.83 47.62,86.83 47.62,76.03 46.35,74.77 OUT7-8.12
N$119
  Bottom 0.254: IC8.6 66.03,72.22 64.77,73.5 52.7,73.5 52.07,72.86 48.26,72.86 47.62,73.5 47.62,76.03 46.35,76.03 OUT7-8.14
N$120  (via drill 0.61)
  Top 0.254: v74.29,75.4 74.29,72.86 IC8.9 | v67.94,86.83 v67.94,75.4 | v46.35,86.83 46.35,79.84 OUT7-8.16
  Bottom 0.254: v67.94,75.4 v74.29,75.4 | v67.94,86.83 67.94,87.47 46.98,87.47 v46.35,86.83
N$121  (via drill 0.61)
  Top 0.254: v50.16,62.7 v50.16,67.78 | v74.29,63.34 74.29,60.16 IC7.9
  Bottom 0.254: v50.16,67.78 46.98,67.78 46.35,68.41 OUT7-8.8 | v50.16,62.7 52.7,62.7 53.34,62.06 67.94,62.06 69.21,63.34 v74.29,63.34
N$122  (via drill 0.61)
  Top 0.254: v50.16,39.84 50.16,55.71 49.53,56.35 49.53,58.89 47.62,60.8 47.62,62.06 46.98,62.7 45.72,62.7 45.08,63.34 45.08,65.88 45.72,66.51 OUT7-8.6 | v65.4,39.84 65.4,54.45 66.67,55.71 66.67,57.62 IC7.6
  Bottom 0.254: v50.16,39.84 50.8,39.2 60.96,39.2 61.59,39.84 v65.4,39.84
N$123
  Top 0.254: IC7.5 64.13,60.16 65.4,61.43 65.4,67.78 67.94,70.32 67.94,74.13 70.48,76.67 70.48,85.56 67.94,88.1 45.08,88.1 45.08,81.75 45.72,81.11 45.72,80.48 45.08,79.84 45.08,70.95 45.72,70.32 47.62,70.32 47.62,65.88 46.35,64.61 OUT7-8.4
OSEL
  Bottom 0.254: IC10.18 64.13,44.92 65.4,46.19 65.4,50 72.38,50 73.66,51.27 JP1.4
OUT00  (via drill 0.61)
  Top 0.254: v47.62,15.71 47.62,24.6 48.89,25.87 48.89,27.14 IC10.1
  Bottom 0.254: v47.62,15.71 39.37,15.71 IC1.11
OUT01
  Bottom 0.254: IC2.11 39.37,27.77 40.64,26.5 49.53,26.5 50.8,27.77 IC10.2
OUT02
  Bottom 0.254: IC3.11 38.73,39.84 38.73,35.39 38.1,35.39 37.46,34.76 37.46,30.31 52.07,30.31 53.34,29.04 IC10.3
OUT03  (via drill 0.61)
  Top 0.254: v57.78,37.3 57.15,36.66 57.15,29.04 IC10.4 | v40,37.3 40,48.09 38.73,49.37 38.73,52.54 IC4.11
  Bottom 0.254: v57.78,37.3 57.15,37.94 47.62,37.94 46.98,37.3 v40,37.3
OUT04  (via drill 0.61)
  Top 0.254: v60.32,36.03 59.69,35.39 59.69,29.04 IC10.5 | v41.27,36.03 41.27,37.3 40.64,37.94 40.64,56.98 41.27,57.62 41.27,85.56 41.91,86.19 41.91,86.83 40.64,88.1 39.37,88.1 39.37,86.19 40,85.56 40,74.77 v39.37,74.13 | v38.73,69.05 38.73,67.78 IC5.11
  Bottom 0.254: v41.27,36.03 v60.32,36.03 | v39.37,74.13 39.37,73.5 40,72.86 40,69.05 v38.73,69.05
OUT05  (via drill 0.61)
  Top 0.254: v61.59,34.76 61.59,29.68 IC10.6 | v45.08,34.76 45.08,62.06 43.81,63.34 43.81,68.41 v44.45,69.05 | v38.73,75.4 38.73,77.94 IC6.11
  Bottom 0.254: v61.59,34.76 60.32,34.76 59.69,35.39 45.72,35.39 v45.08,34.76 | v44.45,69.05 40.64,72.86 40.64,75.4 v38.73,75.4
OUT06
  Top 0.254: IC10.7 64.13,27.14 62.86,25.87 62.86,19.52 73.02,9.36 73.02,6.82 74.29,5.55 78.73,5.55 78.73,50 78.1,50.63 78.1,60.8 76.83,62.06 76.83,65.24 IC7.11
OUT07  (via drill 0.61)
  Top 0.254: v66.67,41.11 66.67,29.68 IC10.8 | v75.56,41.11 v75.56,50 | v79.37,50.63 78.73,51.27 78.73,61.43 77.46,62.7 77.46,64.61 78.1,65.24 78.1,72.86 76.83,74.13 76.83,77.94 IC8.11
  Bottom 0.254: v66.67,41.11 v75.56,41.11 | v75.56,50 78.73,50 v79.37,50.63
PIA-A0  (via drill 0.61)
  Top 0.254: IC1.3 20.95,9.36 20.95,11.27 22.22,12.54 22.22,16.98 21.58,17.61 21.58,20.15 IC2.3 21.58,21.42 21.58,22.7 22.22,23.33 22.22,29.68 21.58,30.31 21.58,32.85 IC3.3 21.58,34.12 21.58,35.39 22.22,36.03 22.22,42.38 21.58,43.02 21.58,45.55 IC4.3 21.58,46.82 21.58,48.09 22.22,48.73 v22.22,51.27 22.22,55.08 21.58,55.71 21.58,58.25 IC5.3 21.58,59.52 21.58,60.8 22.22,61.43 22.22,67.78 21.58,68.41 21.58,70.95 IC6.3 | 57.78,60.16 58.41,59.52 IC7.3 | 57.78,60.16 57.78,67.78 59.05,69.05 59.05,70.32 IC8.3 | 93.34,19.52 92.7,20.15 IC12.2 | 93.34,19.52 93.34,12.54 92.07,11.27 92.07,9.36 IC11.2 | 93.34,32.22 92.7,32.85 IC13.2 | 93.34,32.22 93.34,19.52 | 93.34,44.92 92.7,45.55 IC14.2 | 93.34,44.92 93.34,32.22 | 93.34,57.62 92.7,58.25 IC15.2 | 93.34,57.62 93.34,44.92 | 93.34,57.62 93.34,70.32 92.7,70.95 IC16.2 | v57.78,52.54 57.78,60.16
  Bottom 0.254: v22.22,51.27 45.72,51.27 SV9.1 46.35,51.91 46.98,52.54 v57.78,52.54 | IC7.3 59.05,57.62 59.69,56.98 91.44,56.98 92.07,57.62 IC15.2
PIA-A1  (via drill 0.61)
  Top 0.254: IC11.5 99.69,9.36 99.69,11.27 100.96,12.54 100.96,16.98 100.32,17.61 100.32,20.15 IC12.5 100.32,21.42 100.32,22.7 100.96,23.33 100.96,29.68 100.32,30.31 100.32,32.85 IC13.5 100.32,34.12 100.32,35.39 100.96,36.03 100.96,42.38 100.32,43.02 100.32,45.55 IC14.5 100.32,46.82 100.32,48.09 100.96,48.73 100.96,55.08 100.32,55.71 100.32,58.25 IC15.5 100.32,59.52 100.32,60.8 100.96,61.43 100.96,67.78 100.32,68.41 100.32,70.95 IC16.5 100.32,72.22 100.32,77.3 100.96,77.94 v100.96,83.02 | IC7.4 62.23,59.52 62.86,60.16 62.86,67.78 61.59,69.05 61.59,70.32 IC8.4 61.59,72.86 61.59,74.13 62.23,74.77 62.23,77.3 62.86,77.94 62.86,84.92 v62.23,85.56 | v46.35,59.52 46.35,54.45 SV9.2 | 24.76,19.52 24.12,20.15 IC2.4 | 24.76,19.52 24.76,12.54 23.49,11.27 23.49,9.36 IC1.4 | 24.76,32.22 24.12,32.85 IC3.4 | 24.76,19.52 24.76,32.22 | 24.76,44.92 24.12,45.55 IC4.4 | 24.76,32.22 24.76,44.92 | 24.76,57.62 24.12,58.25 IC5.4 | 24.76,44.92 24.76,57.62 | 24.76,57.62 24.76,70.32 24.12,70.95 IC6.4 | v42.54,44.28 v42.54,53.81 | v73.02,87.47 v73.02,83.02
  Bottom 0.254: v46.35,59.52 50.8,59.52 51.43,60.16 52.7,60.16 53.34,60.8 60.96,60.8 61.59,60.16 IC7.4 | v42.54,53.81 45.72,53.81 SV9.2 | v42.54,44.28 24.12,44.28 23.49,44.92 IC4.4 | v100.96,83.02 100.32,82.39 73.66,82.39 v73.02,83.02 | v73.02,87.47 72.38,86.83 69.84,86.83 68.57,85.56 v62.23,85.56
PIA-A2  (via drill 0.61)
  Top 0.254: IC6.7 31.11,70.32 31.11,69.69 32.38,68.41 32.38,65.24 31.74,64.61 31.74,59.52 IC5.7 31.74,58.25 31.74,55.71 32.38,55.08 v32.38,50 32.38,48.73 31.74,48.09 31.74,46.82 IC4.7 31.11,44.92 31.11,44.28 32.38,43.02 32.38,39.84 31.74,39.2 31.74,34.12 IC3.7 31.11,32.22 31.11,31.58 32.38,30.31 32.38,27.14 31.74,26.5 31.74,21.42 IC2.7 31.11,19.52 31.11,18.88 32.38,17.61 32.38,9.36 31.74,8.73 IC1.7 31.11,6.82 v31.11,2.38 | IC8.7 69.21,70.32 69.21,69.05 67.94,67.78 67.94,60.16 68.57,59.52 IC7.7 69.21,60.16 v69.21,62.06 | IC13.6 102.86,32.85 102.86,31.58 103.5,30.95 103.5,27.14 102.86,26.5 102.86,21.42 IC12.6 102.23,19.52 102.23,18.88 102.86,18.25 102.86,17.61 103.5,16.98 103.5,14.44 102.23,13.17 102.23,9.36 IC11.6 102.23,6.82 v102.23,4.92 102.23,1.74 113.66,1.74 116.2,4.28 116.2,4.92 115.56,5.55 115.56,8.09 116.2,8.73 116.2,15.71 115.56,16.34 115.56,27.14 116.2,27.77 116.2,28.41 115.56,29.04 115.56,40.48 116.2,41.11 v116.2,44.92 | v82.55,60.16 82.55,50 83.18,49.37 83.18,32.85 v82.55,32.22
  Bottom 0.254: v32.38,50 33.02,50.63 34.92,50.63 35.55,50 46.98,50 47.62,50.63 48.89,50.63 SV9.3 | v69.21,62.06 69.84,61.43 76.83,61.43 78.1,60.16 v82.55,60.16 87.62,60.16 88.26,60.8 101.59,60.8 102.23,60.16 IC15.6 | IC16.6 102.23,70.32 102.23,69.05 94.61,69.05 93.97,69.69 69.84,69.69 69.21,70.32 IC8.7 | v116.2,44.92 113.66,44.92 113.02,44.28 102.86,44.28 102.23,44.92 IC14.6 | v82.55,32.22 83.81,32.22 84.45,31.58 101.59,31.58 102.23,32.22 IC13.6 | v31.11,2.38 31.74,1.74 92.7,1.74 95.88,4.92 v102.23,4.92
PIA-A3  (via drill 0.61)
  Top 0.254: IC1.8 34.29,8.73 34.92,9.36 34.92,16.98 34.29,17.61 34.29,18.25 33.65,18.88 33.65,19.52 IC2.8 34.29,21.42 34.29,26.5 34.92,27.14 34.92,29.68 34.29,30.31 34.29,30.95 33.65,31.58 33.65,32.22 IC3.8 34.29,34.12 34.29,39.2 34.92,39.84 34.92,42.38 34.29,43.02 34.29,43.65 33.65,44.28 33.65,44.92 IC4.8 34.29,46.82 34.29,48.09 34.92,48.73 v34.92,49.37 34.92,55.08 34.29,55.71 34.29,58.25 IC5.8 34.29,59.52 34.29,64.61 34.92,65.24 34.92,67.78 34.29,68.41 34.29,69.05 33.65,69.69 33.65,70.32 IC6.8 34.29,72.22 34.29,77.3 34.92,77.94 v34.92,82.39 | v47.62,49.37 47.62,53.17 48.26,53.81 SV9.4 | IC11.9 110.48,8.73 111.12,9.36 111.12,16.98 110.48,17.61 110.48,20.15 IC12.9 109.85,22.06 109.85,24.6 110.48,25.23 110.48,26.5 111.12,27.14 111.12,32.22 110.48,32.85 IC13.9 109.21,32.85 106.67,30.31 104.13,30.31 104.13,31.58 103.5,32.22 103.5,56.35 | 108.58,56.35 108.58,47.46 109.21,46.82 IC14.9 | 108.58,56.35 109.21,56.98 109.21,58.25 IC15.9 | IC7.8 72.38,59.52 73.02,60.16 73.02,67.78 71.75,69.05 71.75,70.32 IC8.8 71.75,72.86 71.75,74.13 72.38,74.77 72.38,77.3 73.02,77.94 v73.02,81.75 | v106.04,83.66 106.04,84.92 107.31,84.92 111.12,81.11 111.12,77.94 110.48,77.3 110.48,72.22 IC16.9 | 103.5,56.35 108.58,56.35 | v103.5,82.39 103.5,56.35
  Bottom 0.254: v34.92,49.37 v47.62,49.37 | v106.04,83.66 104.77,83.66 v103.5,82.39 102.86,81.75 v73.02,81.75 72.38,82.39 65.4,82.39 64.77,81.75 48.26,81.75 47.62,82.39 v34.92,82.39
PIA-A4  (via drill 0.61)
  Top 0.254: IC11.12 109.85,16.98 109.85,18.25 108.58,19.52 108.58,24.6 109.85,25.87 109.85,27.14 IC12.12 | IC15.12 109.21,67.14 109.21,69.69 108.58,70.32 108.58,73.5 109.85,74.77 109.85,77.94 IC16.12 | v125.72,29.68 126.99,30.95 126.99,81.11 v125.72,82.39 | IC7.13 71.11,67.14 70.48,67.78 70.48,74.13 71.75,75.4 71.75,77.94 IC8.13 71.75,80.48 v71.75,83.66 | IC1.13 33.65,16.98 33.65,17.61 32.38,18.88 32.38,22.06 33.65,23.33 33.65,27.14 IC2.13 33.65,29.68 33.65,30.31 32.38,31.58 32.38,34.76 33.65,36.03 33.65,39.84 IC3.13 33.65,42.38 33.65,43.02 32.38,44.28 32.38,47.46 v33.65,48.73 33.65,52.54 IC4.13 33.65,55.08 33.65,55.71 32.38,56.98 32.38,60.16 33.65,61.43 33.65,65.24 IC5.13 33.65,67.78 33.65,68.41 32.38,69.69 32.38,72.86 33.65,74.13 33.65,77.94 IC6.13 33.65,80.48 v33.65,83.66 | v106.04,37.94 106.04,36.66 106.67,36.03 107.31,36.03 109.21,37.94 109.21,40.48 IC13.12 | v81.91,38.57 82.55,39.2 82.55,48.73 81.91,49.37 81.91,59.52 81.27,60.16 v81.27,67.78 | v80,39.2 v80,49.37
  Bottom 0.254: v125.72,29.68 116.83,29.68 116.2,30.31 110.48,30.31 109.85,29.68 IC12.12 | v125.72,82.39 126.99,81.11 126.99,79.84 125.72,79.84 125.09,80.48 113.66,80.48 113.02,81.11 111.75,81.11 | 111.75,81.11 111.12,80.48 109.85,80.48 IC16.12 | v33.65,48.73 34.29,48.09 34.92,48.09 35.55,48.73 46.35,48.73 46.98,48.09 47.62,48.09 48.89,49.37 50.16,49.37 51.43,50.63 SV9.5 | v71.75,83.66 71.11,83.02 64.77,83.02 64.13,82.39 48.89,82.39 48.26,83.02 35.55,83.02 34.92,83.66 v33.65,83.66 | v106.04,37.94 95.24,37.94 94.61,38.57 v81.91,38.57 80.64,38.57 v80,39.2 | v81.27,67.78 80.64,68.41 72.38,68.41 71.75,67.78 IC7.13 | v80,49.37 84.45,49.37 85.08,50 95.88,50 97.78,51.91 107.94,51.91 108.58,52.54 109.85,52.54 IC14.12 | 111.75,81.11 73.66,81.11 73.02,80.48 71.75,80.48 IC8.13
PIA-A5
  Top 0.254: 29.84,25.87 29.84,18.25 31.11,16.98 IC1.14 | 29.84,25.87 31.11,27.14 IC2.14 | 29.84,38.57 31.11,39.84 IC3.14 | 29.84,25.87 29.84,38.57 | 29.84,51.27 31.11,52.54 IC4.14 | 29.84,38.57 29.84,51.27 | 29.84,63.97 31.11,65.24 IC5.14 | 29.84,51.27 29.84,63.97 | 29.84,63.97 29.84,76.67 31.11,77.94 IC6.14 | IC11.15 102.23,16.98 100.96,18.25 100.96,22.06 102.23,23.33 102.23,27.14 IC12.15 102.23,29.68 100.96,30.95 100.96,34.76 102.23,36.03 102.23,39.84 IC13.15 102.23,42.38 100.96,43.65 100.96,47.46 102.23,48.73 102.23,52.54 IC14.15 102.23,55.08 100.96,56.35 100.96,60.16 102.23,61.43 102.23,65.24 IC15.15 102.23,67.78 100.96,69.05 100.96,76.67 102.23,77.94 IC16.15
  Bottom 0.254: SV9.6 50.8,53.81 49.53,55.08 42.54,55.08 39.37,51.91 33.02,51.91 31.74,53.17 IC4.14 | IC15.15 101.59,67.14 100.32,68.41 93.97,68.41 93.34,69.05 71.75,69.05 69.84,67.14 IC7.14 69.21,67.78 67.94,67.78 67.94,72.86 67.3,73.5 66.67,73.5 66.67,75.4 69.21,77.94 IC8.14 68.57,79.84 67.3,81.11 46.35,81.11 42.54,77.3 33.02,77.3 31.74,78.58 IC6.14
PIA-A6  (via drill 0.61)
  Top 0.254: IC1.17 22.86,16.34 22.86,17.61 22.22,18.25 22.22,22.06 22.86,22.7 22.86,27.77 IC2.17 22.86,29.04 22.86,30.31 22.22,30.95 22.22,34.76 22.86,35.39 22.86,40.48 IC3.17 | v52.7,45.55 52.7,50.63 53.34,51.27 SV9.7 | v23.49,43.65 23.49,42.38 IC3.17 | IC3.17 22.86,41.74 22.86,43.02 22.22,43.65 22.22,47.46 22.86,48.09 22.86,48.73 23.49,49.37 23.49,52.54 IC4.17 22.86,54.45 22.86,55.71 22.22,56.35 22.22,60.16 22.86,60.8 22.86,65.88 IC5.17 22.86,67.14 22.86,68.41 22.22,69.05 22.22,72.86 23.49,74.13 23.49,77.94 IC6.17 23.49,80.48 v23.49,86.83 | IC11.16 99.05,16.34 99.05,18.25 98.42,18.88 98.42,22.06 99.69,23.33 99.69,27.14 IC12.16 99.69,29.68 99.69,30.31 98.42,31.58 98.42,34.76 99.69,36.03 99.69,39.84 IC13.16 99.69,42.38 99.69,43.65 98.42,44.92 98.42,47.46 99.69,48.73 99.69,52.54 IC14.16 99.05,54.45 98.42,55.08 98.42,60.16 99.69,61.43 99.69,65.24 IC15.16 99.05,67.14 98.42,67.78 98.42,72.86 99.69,74.13 99.69,77.94 IC16.16 99.69,80.48 v99.69,83.66 | IC7.17 60.96,67.14 60.96,69.69 60.32,70.32 60.32,72.86 60.96,73.5 60.96,74.77 61.59,75.4 61.59,77.94 IC8.17 60.96,79.84 v60.96,84.92 | v76.83,87.47 v76.83,83.66
  Bottom 0.254: v52.7,45.55 45.08,45.55 42.54,43.02 41.91,43.02 41.27,43.65 v23.49,43.65 | 61.59,84.29 v60.96,84.92 | 61.59,84.29 62.23,84.29 62.86,84.92 69.21,84.92 70.48,86.19 73.02,86.19 74.29,87.47 v76.83,87.47 | v76.83,83.66 77.46,83.02 99.05,83.02 v99.69,83.66 | v23.49,86.83 24.12,86.19 34.92,86.19 36.19,87.47 44.45,87.47 46.35,85.56 50.16,85.56 51.43,84.29 61.59,84.29
PIA-A7  (via drill 0.61)
  Top 0.254: IC11.19 92.07,16.98 92.07,17.61 90.8,18.88 90.8,22.06 92.07,23.33 92.07,27.14 IC12.19 92.07,29.68 92.07,30.31 90.8,31.58 90.8,34.76 92.07,36.03 92.07,39.84 IC13.19 92.07,42.38 92.07,43.02 90.8,44.28 90.8,47.46 92.07,48.73 92.07,52.54 IC14.19 92.07,55.08 92.07,55.71 90.8,56.98 90.8,60.16 92.07,61.43 92.07,65.24 IC15.19 92.07,67.78 92.07,68.41 90.8,69.69 90.8,72.86 92.07,74.13 92.07,77.94 IC16.19 | v57.78,69.05 57.78,74.13 59.05,75.4 59.05,77.94 IC8.18 | IC1.18 20.95,16.98 20.95,17.61 19.68,18.88 19.68,22.06 20.95,23.33 20.95,27.14 IC2.18 20.95,29.68 20.95,30.31 19.68,31.58 19.68,34.76 20.95,36.03 20.95,39.84 IC3.18 20.95,42.38 20.95,43.02 19.68,44.28 19.68,47.46 20.95,48.73 20.95,52.54 IC4.18 20.95,55.08 20.95,55.71 19.68,56.98 19.68,60.16 20.95,61.43 20.95,65.24 IC5.18 20.95,67.78 20.95,68.41 19.68,69.69 19.68,72.86 20.95,74.13 20.95,77.94 IC6.18 | v60.32,55.08 60.32,61.43 59.05,62.7 59.05,65.24 IC7.18
  Bottom 0.254: v57.78,69.05 59.05,67.78 IC7.18 | 53.97,54.45 52.7,54.45 51.43,55.71 21.58,55.71 20.95,55.08 IC4.18 | 53.97,54.45 SV9.8 53.97,54.45 | 59.05,55.08 54.61,55.08 53.97,54.45 | 59.05,55.08 v60.32,55.08 | 59.05,55.08 59.69,55.71 81.91,55.71 85.72,51.91 91.44,51.91 92.07,52.54 IC14.19
PIA-B0
  Top 0.254: IC10.23 51.43,42.38 51.43,39.84 50.16,38.57 50.16,25.87 51.43,24.6 IC9.23 51.43,22.06 51.43,21.42 59.69,21.42 60.32,22.06 60.32,24.6 62.86,27.14 62.86,46.82 61.59,48.09 61.59,50.63 SV9.13
PIA-B1  (via drill 0.61)
  Top 0.254: IC9.22 53.97,24.6 53.97,25.23 52.7,26.5 52.7,29.68 53.97,30.95 53.97,42.38 IC10.22 53.97,44.92 v53.97,49.37 | v62.86,49.37 62.86,51.91 62.23,52.54 62.23,53.81 SV9.14
  Bottom 0.254: v53.97,49.37 v62.86,49.37
PIA-B2
  Top 0.254: IC9.21 56.51,24.6 55.24,25.87 55.24,41.11 56.51,42.38 IC10.21
  Bottom 0.254: SV9.15 64.13,50.63 64.13,46.19 62.23,46.19 61.59,45.55 58.41,45.55 57.15,44.28 IC10.21
PIA-B3  (via drill 0.61)
  Top 0.254: IC9.20 59.05,24.6 59.05,25.23 57.78,26.5 57.78,29.68 59.05,30.95 59.05,42.38 IC10.20 59.05,44.92 59.05,46.82 60.32,48.09 v60.32,52.54
  Bottom 0.254: v60.32,52.54 63.5,52.54 64.13,53.17 SV9.16
PIA-B4  (via drill 0.61)
  Top 0.254: v66.67,47.46 66.67,50.63 SV9.17
  Bottom 0.254: v66.67,47.46 76.19,47.46 76.83,48.09 JP1.1
PIA-B5  (via drill 0.61)
  Top 0.254: v67.94,48.73 67.94,51.91 67.3,52.54 67.3,53.81 SV9.18
  Bottom 0.254: v67.94,48.73 73.66,48.73 JP1.2
PIA-B6
  Bottom 0.254: JP1.5 76.19,53.81 74.92,52.54 71.11,52.54 69.84,51.27 SV9.19
PIA-B7
  Bottom 0.254: JP1.6 73.66,53.81 69.84,53.81 SV9.20
VCC  (via drill 0.61)
  Top 0.508: v114.93,15.71 v114.93,28.41 v114.93,41.11 v114.93,53.81 | 112.39,76.03 113.66,74.77 113.66,67.78 113.02,67.14 IC15.11 | 112.39,76.03 112.39,77.94 IC16.11 | 85.72,66.51 86.35,66.51 BYP15.1 | 85.72,66.51 85.72,78.58 86.35,79.21 BYP16.1 | v112.39,75.4 112.39,76.03 | v89.53,75.4 89.53,77.94 IC16.20 | IC11.20 88.89,16.34 88.26,16.98 88.26,24.6 86.99,25.87 86.99,27.77 BYP12.1 86.99,29.04 86.99,33.49 88.26,34.76 88.26,37.3 86.99,38.57 86.99,40.48 BYP13.1 86.99,41.74 86.99,46.82 89.53,49.37 89.53,52.54 IC14.20 | 85.72,66.51 85.72,57.62 86.99,56.35 86.99,54.45 BYP14.1 | v122.55,65.24 v122.55,52.54 | BYP9.1 46.35,23.96 46.35,31.58 47.62,32.85 47.62,37.94 48.89,39.2 48.89,42.38 IC10.24 48.89,44.92 v48.89,48.09 | BYP7.1 51.43,67.14 51.43,70.32 52.7,71.59 52.7,73.5 53.97,74.77 53.97,77.94 IC8.20 | BYP1.1 13.33,16.34 13.33,19.52 14.6,20.79 14.6,22.06 15.87,23.33 15.87,27.14 IC2.20 | BYP3.1 13.33,41.74 13.33,44.92 14.6,46.19 14.6,47.46 15.87,48.73 15.87,52.54 IC4.20 | IC5.20 15.87,65.24 15.87,61.43 14.6,60.16 14.6,58.89 13.33,57.62 13.33,54.45 BYP4.1 | IC6.20 15.87,77.94 15.87,74.77 14.6,73.5 14.6,71.59 13.33,70.32 13.33,67.14 BYP5.1 | v59.05,56.35 59.05,54.45 SV9.12 59.05,53.17 59.05,51.91 SV9.11 59.05,50.63 v59.05,48.09 | BYP2.1 13.33,29.04 13.33,32.22 14.6,33.49 14.6,34.76 15.87,36.03 15.87,39.84 IC3.20 | v52.7,55.71 52.7,60.16 53.97,61.43 53.97,65.24 IC7.20
  Bottom 0.508: v114.93,15.71 113.02,15.71 IC11.11 | v114.93,41.11 113.02,41.11 IC13.11 | v114.93,28.41 113.02,28.41 IC12.11 | v114.93,53.81 113.02,53.81 IC14.11 112.39,55.08 118.1,55.08 118.74,54.45 118.74,53.17 119.38,52.54 v122.55,52.54 | BYP15.1 87.62,66.51 88.89,66.51 IC15.20 | BYP16.1 87.62,79.21 88.89,79.21 IC16.20 | v89.53,75.4 v112.39,75.4 | BYP11.1 87.62,15.71 88.89,15.71 IC11.20 | BYP12.1 87.62,28.41 88.89,28.41 IC12.20 | BYP13.1 87.62,41.11 88.89,41.11 IC13.20 | BYP14.1 87.62,53.81 88.89,53.81 IC14.20 89.53,55.08 88.26,56.35 v59.05,56.35 52.7,56.35 | v122.55,65.24 119.38,65.24 118.74,65.88 118.74,67.14 118.1,67.78 116.83,67.78 116.2,67.14 113.02,67.14 IC15.11 | BYP9.1 46.98,23.33 48.26,23.33 IC9.24 | BYP10.1 46.98,43.65 48.26,43.65 IC10.24 | BYP7.1 52.07,66.51 53.34,66.51 IC7.20 | BYP8.1 52.07,79.21 53.34,79.21 IC8.20 | BYP1.1 13.97,15.71 15.24,15.71 IC1.20 | BYP2.1 13.97,28.41 15.24,28.41 IC2.20 | BYP6.1 13.97,79.21 15.24,79.21 IC6.20 | BYP5.1 13.97,66.51 15.24,66.51 IC5.20 | BYP3.1 13.97,41.11 15.24,41.11 IC3.20 | BYP4.1 13.97,53.81 15.24,53.81 IC4.20 15.87,55.08 16.5,55.71 17.77,55.71 18.41,56.35 52.7,56.35 | 52.7,56.35 v52.7,55.71 | v59.05,48.09 v48.89,48.09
